VERSION 5.8 ;
BUSBITCHARS "[]" ;
DIVIDERCHAR "/" ;
UNITS
    DATABASE MICRONS 1000 ;
END UNITS

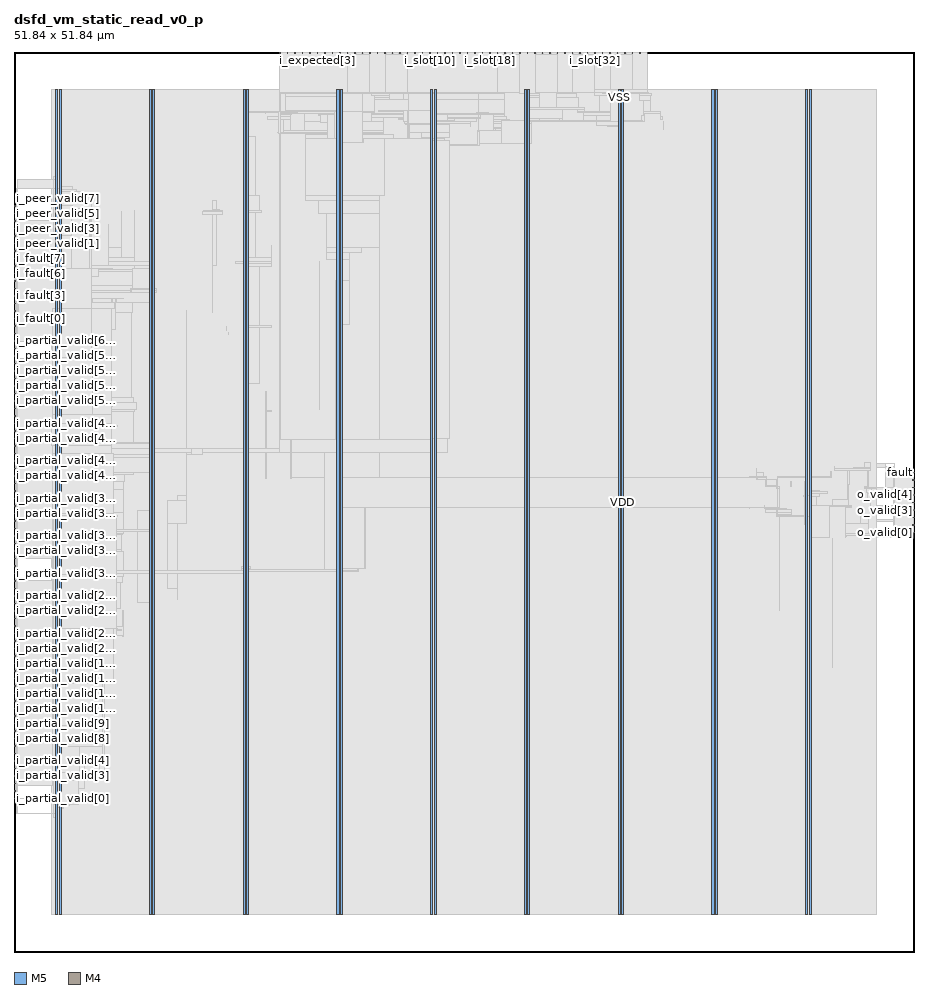
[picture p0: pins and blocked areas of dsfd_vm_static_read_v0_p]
MACRO dsfd_vm_static_read_v0_p
  FOREIGN dsfd_vm_static_read_v0_p 0 0 ;
  CLASS BLOCK ;
  SIZE 51.84 BY 51.84 ;
  PIN ck
    DIRECTION INPUT ;
    USE SIGNAL ;
    PORT
      LAYER M5 ;
        RECT  15.312 51.756 15.336 51.84 ;
    END
  END ck
  PIN fault
    DIRECTION OUTPUT ;
    USE SIGNAL ;
    PORT
      LAYER M4 ;
        RECT  51.756 27.6 51.84 27.624 ;
    END
  END fault
  PIN i_expected[0]
    DIRECTION INPUT ;
    USE SIGNAL ;
    PORT
      LAYER M5 ;
        RECT  16.176 51.756 16.2 51.84 ;
    END
  END i_expected[0]
  PIN i_expected[1]
    DIRECTION INPUT ;
    USE SIGNAL ;
    PORT
      LAYER M5 ;
        RECT  16.608 51.756 16.632 51.84 ;
    END
  END i_expected[1]
  PIN i_expected[2]
    DIRECTION INPUT ;
    USE SIGNAL ;
    PORT
      LAYER M5 ;
        RECT  17.04 51.756 17.064 51.84 ;
    END
  END i_expected[2]
  PIN i_expected[3]
    DIRECTION INPUT ;
    USE SIGNAL ;
    PORT
      LAYER M5 ;
        RECT  17.472 51.756 17.496 51.84 ;
    END
  END i_expected[3]
  PIN i_expected[4]
    DIRECTION INPUT ;
    USE SIGNAL ;
    PORT
      LAYER M5 ;
        RECT  17.904 51.756 17.928 51.84 ;
    END
  END i_expected[4]
  PIN i_expected[5]
    DIRECTION INPUT ;
    USE SIGNAL ;
    PORT
      LAYER M5 ;
        RECT  18.336 51.756 18.36 51.84 ;
    END
  END i_expected[5]
  PIN i_expected[6]
    DIRECTION INPUT ;
    USE SIGNAL ;
    PORT
      LAYER M5 ;
        RECT  18.768 51.756 18.792 51.84 ;
    END
  END i_expected[6]
  PIN i_expected[7]
    DIRECTION INPUT ;
    USE SIGNAL ;
    PORT
      LAYER M5 ;
        RECT  19.2 51.756 19.224 51.84 ;
    END
  END i_expected[7]
  PIN i_fault[0]
    DIRECTION INPUT ;
    USE SIGNAL ;
    PORT
      LAYER M4 ;
        RECT  0 36.48 0.084 36.504 ;
    END
  END i_fault[0]
  PIN i_fault[1]
    DIRECTION INPUT ;
    USE SIGNAL ;
    PORT
      LAYER M4 ;
        RECT  0 36.912 0.084 36.936 ;
    END
  END i_fault[1]
  PIN i_fault[2]
    DIRECTION INPUT ;
    USE SIGNAL ;
    PORT
      LAYER M4 ;
        RECT  0 37.344 0.084 37.368 ;
    END
  END i_fault[2]
  PIN i_fault[3]
    DIRECTION INPUT ;
    USE SIGNAL ;
    PORT
      LAYER M4 ;
        RECT  0 37.776 0.084 37.8 ;
    END
  END i_fault[3]
  PIN i_fault[4]
    DIRECTION INPUT ;
    USE SIGNAL ;
    PORT
      LAYER M4 ;
        RECT  0 38.208 0.084 38.232 ;
    END
  END i_fault[4]
  PIN i_fault[5]
    DIRECTION INPUT ;
    USE SIGNAL ;
    PORT
      LAYER M4 ;
        RECT  0 38.64 0.084 38.664 ;
    END
  END i_fault[5]
  PIN i_fault[6]
    DIRECTION INPUT ;
    USE SIGNAL ;
    PORT
      LAYER M4 ;
        RECT  0 39.072 0.084 39.096 ;
    END
  END i_fault[6]
  PIN i_fault[7]
    DIRECTION INPUT ;
    USE SIGNAL ;
    PORT
      LAYER M4 ;
        RECT  0 39.504 0.084 39.528 ;
    END
  END i_fault[7]
  PIN i_partial_valid[0]
    DIRECTION INPUT ;
    USE SIGNAL ;
    PORT
      LAYER M4 ;
        RECT  0 8.832 0.084 8.856 ;
    END
  END i_partial_valid[0]
  PIN i_partial_valid[10]
    DIRECTION INPUT ;
    USE SIGNAL ;
    PORT
      LAYER M4 ;
        RECT  0 13.152 0.084 13.176 ;
    END
  END i_partial_valid[10]
  PIN i_partial_valid[11]
    DIRECTION INPUT ;
    USE SIGNAL ;
    PORT
      LAYER M4 ;
        RECT  0 13.584 0.084 13.608 ;
    END
  END i_partial_valid[11]
  PIN i_partial_valid[12]
    DIRECTION INPUT ;
    USE SIGNAL ;
    PORT
      LAYER M4 ;
        RECT  0 14.016 0.084 14.04 ;
    END
  END i_partial_valid[12]
  PIN i_partial_valid[13]
    DIRECTION INPUT ;
    USE SIGNAL ;
    PORT
      LAYER M4 ;
        RECT  0 14.448 0.084 14.472 ;
    END
  END i_partial_valid[13]
  PIN i_partial_valid[14]
    DIRECTION INPUT ;
    USE SIGNAL ;
    PORT
      LAYER M4 ;
        RECT  0 14.88 0.084 14.904 ;
    END
  END i_partial_valid[14]
  PIN i_partial_valid[15]
    DIRECTION INPUT ;
    USE SIGNAL ;
    PORT
      LAYER M4 ;
        RECT  0 15.312 0.084 15.336 ;
    END
  END i_partial_valid[15]
  PIN i_partial_valid[16]
    DIRECTION INPUT ;
    USE SIGNAL ;
    PORT
      LAYER M4 ;
        RECT  0 15.744 0.084 15.768 ;
    END
  END i_partial_valid[16]
  PIN i_partial_valid[17]
    DIRECTION INPUT ;
    USE SIGNAL ;
    PORT
      LAYER M4 ;
        RECT  0 16.176 0.084 16.2 ;
    END
  END i_partial_valid[17]
  PIN i_partial_valid[18]
    DIRECTION INPUT ;
    USE SIGNAL ;
    PORT
      LAYER M4 ;
        RECT  0 16.608 0.084 16.632 ;
    END
  END i_partial_valid[18]
  PIN i_partial_valid[19]
    DIRECTION INPUT ;
    USE SIGNAL ;
    PORT
      LAYER M4 ;
        RECT  0 17.04 0.084 17.064 ;
    END
  END i_partial_valid[19]
  PIN i_partial_valid[1]
    DIRECTION INPUT ;
    USE SIGNAL ;
    PORT
      LAYER M4 ;
        RECT  0 9.264 0.084 9.288 ;
    END
  END i_partial_valid[1]
  PIN i_partial_valid[20]
    DIRECTION INPUT ;
    USE SIGNAL ;
    PORT
      LAYER M4 ;
        RECT  0 17.472 0.084 17.496 ;
    END
  END i_partial_valid[20]
  PIN i_partial_valid[21]
    DIRECTION INPUT ;
    USE SIGNAL ;
    PORT
      LAYER M4 ;
        RECT  0 17.904 0.084 17.928 ;
    END
  END i_partial_valid[21]
  PIN i_partial_valid[22]
    DIRECTION INPUT ;
    USE SIGNAL ;
    PORT
      LAYER M4 ;
        RECT  0 18.336 0.084 18.36 ;
    END
  END i_partial_valid[22]
  PIN i_partial_valid[23]
    DIRECTION INPUT ;
    USE SIGNAL ;
    PORT
      LAYER M4 ;
        RECT  0 18.768 0.084 18.792 ;
    END
  END i_partial_valid[23]
  PIN i_partial_valid[24]
    DIRECTION INPUT ;
    USE SIGNAL ;
    PORT
      LAYER M4 ;
        RECT  0 19.2 0.084 19.224 ;
    END
  END i_partial_valid[24]
  PIN i_partial_valid[25]
    DIRECTION INPUT ;
    USE SIGNAL ;
    PORT
      LAYER M4 ;
        RECT  0 19.632 0.084 19.656 ;
    END
  END i_partial_valid[25]
  PIN i_partial_valid[26]
    DIRECTION INPUT ;
    USE SIGNAL ;
    PORT
      LAYER M4 ;
        RECT  0 20.064 0.084 20.088 ;
    END
  END i_partial_valid[26]
  PIN i_partial_valid[27]
    DIRECTION INPUT ;
    USE SIGNAL ;
    PORT
      LAYER M4 ;
        RECT  0 20.496 0.084 20.52 ;
    END
  END i_partial_valid[27]
  PIN i_partial_valid[28]
    DIRECTION INPUT ;
    USE SIGNAL ;
    PORT
      LAYER M4 ;
        RECT  0 20.928 0.084 20.952 ;
    END
  END i_partial_valid[28]
  PIN i_partial_valid[29]
    DIRECTION INPUT ;
    USE SIGNAL ;
    PORT
      LAYER M4 ;
        RECT  0 21.36 0.084 21.384 ;
    END
  END i_partial_valid[29]
  PIN i_partial_valid[2]
    DIRECTION INPUT ;
    USE SIGNAL ;
    PORT
      LAYER M4 ;
        RECT  0 9.696 0.084 9.72 ;
    END
  END i_partial_valid[2]
  PIN i_partial_valid[30]
    DIRECTION INPUT ;
    USE SIGNAL ;
    PORT
      LAYER M4 ;
        RECT  0 21.792 0.084 21.816 ;
    END
  END i_partial_valid[30]
  PIN i_partial_valid[31]
    DIRECTION INPUT ;
    USE SIGNAL ;
    PORT
      LAYER M4 ;
        RECT  0 22.224 0.084 22.248 ;
    END
  END i_partial_valid[31]
  PIN i_partial_valid[32]
    DIRECTION INPUT ;
    USE SIGNAL ;
    PORT
      LAYER M4 ;
        RECT  0 22.656 0.084 22.68 ;
    END
  END i_partial_valid[32]
  PIN i_partial_valid[33]
    DIRECTION INPUT ;
    USE SIGNAL ;
    PORT
      LAYER M4 ;
        RECT  0 23.088 0.084 23.112 ;
    END
  END i_partial_valid[33]
  PIN i_partial_valid[34]
    DIRECTION INPUT ;
    USE SIGNAL ;
    PORT
      LAYER M4 ;
        RECT  0 23.52 0.084 23.544 ;
    END
  END i_partial_valid[34]
  PIN i_partial_valid[35]
    DIRECTION INPUT ;
    USE SIGNAL ;
    PORT
      LAYER M4 ;
        RECT  0 23.952 0.084 23.976 ;
    END
  END i_partial_valid[35]
  PIN i_partial_valid[36]
    DIRECTION INPUT ;
    USE SIGNAL ;
    PORT
      LAYER M4 ;
        RECT  0 24.384 0.084 24.408 ;
    END
  END i_partial_valid[36]
  PIN i_partial_valid[37]
    DIRECTION INPUT ;
    USE SIGNAL ;
    PORT
      LAYER M4 ;
        RECT  0 24.816 0.084 24.84 ;
    END
  END i_partial_valid[37]
  PIN i_partial_valid[38]
    DIRECTION INPUT ;
    USE SIGNAL ;
    PORT
      LAYER M4 ;
        RECT  0 25.248 0.084 25.272 ;
    END
  END i_partial_valid[38]
  PIN i_partial_valid[39]
    DIRECTION INPUT ;
    USE SIGNAL ;
    PORT
      LAYER M4 ;
        RECT  0 25.68 0.084 25.704 ;
    END
  END i_partial_valid[39]
  PIN i_partial_valid[3]
    DIRECTION INPUT ;
    USE SIGNAL ;
    PORT
      LAYER M4 ;
        RECT  0 10.128 0.084 10.152 ;
    END
  END i_partial_valid[3]
  PIN i_partial_valid[40]
    DIRECTION INPUT ;
    USE SIGNAL ;
    PORT
      LAYER M4 ;
        RECT  0 26.112 0.084 26.136 ;
    END
  END i_partial_valid[40]
  PIN i_partial_valid[41]
    DIRECTION INPUT ;
    USE SIGNAL ;
    PORT
      LAYER M4 ;
        RECT  0 26.544 0.084 26.568 ;
    END
  END i_partial_valid[41]
  PIN i_partial_valid[42]
    DIRECTION INPUT ;
    USE SIGNAL ;
    PORT
      LAYER M4 ;
        RECT  0 26.976 0.084 27 ;
    END
  END i_partial_valid[42]
  PIN i_partial_valid[43]
    DIRECTION INPUT ;
    USE SIGNAL ;
    PORT
      LAYER M4 ;
        RECT  0 27.408 0.084 27.432 ;
    END
  END i_partial_valid[43]
  PIN i_partial_valid[44]
    DIRECTION INPUT ;
    USE SIGNAL ;
    PORT
      LAYER M4 ;
        RECT  0 27.84 0.084 27.864 ;
    END
  END i_partial_valid[44]
  PIN i_partial_valid[45]
    DIRECTION INPUT ;
    USE SIGNAL ;
    PORT
      LAYER M4 ;
        RECT  0 28.272 0.084 28.296 ;
    END
  END i_partial_valid[45]
  PIN i_partial_valid[46]
    DIRECTION INPUT ;
    USE SIGNAL ;
    PORT
      LAYER M4 ;
        RECT  0 28.704 0.084 28.728 ;
    END
  END i_partial_valid[46]
  PIN i_partial_valid[47]
    DIRECTION INPUT ;
    USE SIGNAL ;
    PORT
      LAYER M4 ;
        RECT  0 29.136 0.084 29.16 ;
    END
  END i_partial_valid[47]
  PIN i_partial_valid[48]
    DIRECTION INPUT ;
    USE SIGNAL ;
    PORT
      LAYER M4 ;
        RECT  0 29.568 0.084 29.592 ;
    END
  END i_partial_valid[48]
  PIN i_partial_valid[49]
    DIRECTION INPUT ;
    USE SIGNAL ;
    PORT
      LAYER M4 ;
        RECT  0 30 0.084 30.024 ;
    END
  END i_partial_valid[49]
  PIN i_partial_valid[4]
    DIRECTION INPUT ;
    USE SIGNAL ;
    PORT
      LAYER M4 ;
        RECT  0 10.56 0.084 10.584 ;
    END
  END i_partial_valid[4]
  PIN i_partial_valid[50]
    DIRECTION INPUT ;
    USE SIGNAL ;
    PORT
      LAYER M4 ;
        RECT  0 30.432 0.084 30.456 ;
    END
  END i_partial_valid[50]
  PIN i_partial_valid[51]
    DIRECTION INPUT ;
    USE SIGNAL ;
    PORT
      LAYER M4 ;
        RECT  0 30.864 0.084 30.888 ;
    END
  END i_partial_valid[51]
  PIN i_partial_valid[52]
    DIRECTION INPUT ;
    USE SIGNAL ;
    PORT
      LAYER M4 ;
        RECT  0 31.296 0.084 31.32 ;
    END
  END i_partial_valid[52]
  PIN i_partial_valid[53]
    DIRECTION INPUT ;
    USE SIGNAL ;
    PORT
      LAYER M4 ;
        RECT  0 31.728 0.084 31.752 ;
    END
  END i_partial_valid[53]
  PIN i_partial_valid[54]
    DIRECTION INPUT ;
    USE SIGNAL ;
    PORT
      LAYER M4 ;
        RECT  0 32.16 0.084 32.184 ;
    END
  END i_partial_valid[54]
  PIN i_partial_valid[55]
    DIRECTION INPUT ;
    USE SIGNAL ;
    PORT
      LAYER M4 ;
        RECT  0 32.592 0.084 32.616 ;
    END
  END i_partial_valid[55]
  PIN i_partial_valid[56]
    DIRECTION INPUT ;
    USE SIGNAL ;
    PORT
      LAYER M4 ;
        RECT  0 33.024 0.084 33.048 ;
    END
  END i_partial_valid[56]
  PIN i_partial_valid[57]
    DIRECTION INPUT ;
    USE SIGNAL ;
    PORT
      LAYER M4 ;
        RECT  0 33.456 0.084 33.48 ;
    END
  END i_partial_valid[57]
  PIN i_partial_valid[58]
    DIRECTION INPUT ;
    USE SIGNAL ;
    PORT
      LAYER M4 ;
        RECT  0 33.888 0.084 33.912 ;
    END
  END i_partial_valid[58]
  PIN i_partial_valid[59]
    DIRECTION INPUT ;
    USE SIGNAL ;
    PORT
      LAYER M4 ;
        RECT  0 34.32 0.084 34.344 ;
    END
  END i_partial_valid[59]
  PIN i_partial_valid[5]
    DIRECTION INPUT ;
    USE SIGNAL ;
    PORT
      LAYER M4 ;
        RECT  0 10.992 0.084 11.016 ;
    END
  END i_partial_valid[5]
  PIN i_partial_valid[60]
    DIRECTION INPUT ;
    USE SIGNAL ;
    PORT
      LAYER M4 ;
        RECT  0 34.752 0.084 34.776 ;
    END
  END i_partial_valid[60]
  PIN i_partial_valid[61]
    DIRECTION INPUT ;
    USE SIGNAL ;
    PORT
      LAYER M4 ;
        RECT  0 35.184 0.084 35.208 ;
    END
  END i_partial_valid[61]
  PIN i_partial_valid[62]
    DIRECTION INPUT ;
    USE SIGNAL ;
    PORT
      LAYER M4 ;
        RECT  0 35.616 0.084 35.64 ;
    END
  END i_partial_valid[62]
  PIN i_partial_valid[63]
    DIRECTION INPUT ;
    USE SIGNAL ;
    PORT
      LAYER M4 ;
        RECT  0 36.048 0.084 36.072 ;
    END
  END i_partial_valid[63]
  PIN i_partial_valid[6]
    DIRECTION INPUT ;
    USE SIGNAL ;
    PORT
      LAYER M4 ;
        RECT  0 11.424 0.084 11.448 ;
    END
  END i_partial_valid[6]
  PIN i_partial_valid[7]
    DIRECTION INPUT ;
    USE SIGNAL ;
    PORT
      LAYER M4 ;
        RECT  0 11.856 0.084 11.88 ;
    END
  END i_partial_valid[7]
  PIN i_partial_valid[8]
    DIRECTION INPUT ;
    USE SIGNAL ;
    PORT
      LAYER M4 ;
        RECT  0 12.288 0.084 12.312 ;
    END
  END i_partial_valid[8]
  PIN i_partial_valid[9]
    DIRECTION INPUT ;
    USE SIGNAL ;
    PORT
      LAYER M4 ;
        RECT  0 12.72 0.084 12.744 ;
    END
  END i_partial_valid[9]
  PIN i_peer_valid[0]
    DIRECTION INPUT ;
    USE SIGNAL ;
    PORT
      LAYER M4 ;
        RECT  0 39.936 0.084 39.96 ;
    END
  END i_peer_valid[0]
  PIN i_peer_valid[1]
    DIRECTION INPUT ;
    USE SIGNAL ;
    PORT
      LAYER M4 ;
        RECT  0 40.368 0.084 40.392 ;
    END
  END i_peer_valid[1]
  PIN i_peer_valid[2]
    DIRECTION INPUT ;
    USE SIGNAL ;
    PORT
      LAYER M4 ;
        RECT  0 40.8 0.084 40.824 ;
    END
  END i_peer_valid[2]
  PIN i_peer_valid[3]
    DIRECTION INPUT ;
    USE SIGNAL ;
    PORT
      LAYER M4 ;
        RECT  0 41.232 0.084 41.256 ;
    END
  END i_peer_valid[3]
  PIN i_peer_valid[4]
    DIRECTION INPUT ;
    USE SIGNAL ;
    PORT
      LAYER M4 ;
        RECT  0 41.664 0.084 41.688 ;
    END
  END i_peer_valid[4]
  PIN i_peer_valid[5]
    DIRECTION INPUT ;
    USE SIGNAL ;
    PORT
      LAYER M4 ;
        RECT  0 42.096 0.084 42.12 ;
    END
  END i_peer_valid[5]
  PIN i_peer_valid[6]
    DIRECTION INPUT ;
    USE SIGNAL ;
    PORT
      LAYER M4 ;
        RECT  0 42.528 0.084 42.552 ;
    END
  END i_peer_valid[6]
  PIN i_peer_valid[7]
    DIRECTION INPUT ;
    USE SIGNAL ;
    PORT
      LAYER M4 ;
        RECT  0 42.96 0.084 42.984 ;
    END
  END i_peer_valid[7]
  PIN i_slot[0]
    DIRECTION INPUT ;
    USE SIGNAL ;
    PORT
      LAYER M5 ;
        RECT  19.632 51.756 19.656 51.84 ;
    END
  END i_slot[0]
  PIN i_slot[10]
    DIRECTION INPUT ;
    USE SIGNAL ;
    PORT
      LAYER M5 ;
        RECT  23.952 51.756 23.976 51.84 ;
    END
  END i_slot[10]
  PIN i_slot[11]
    DIRECTION INPUT ;
    USE SIGNAL ;
    PORT
      LAYER M5 ;
        RECT  24.384 51.756 24.408 51.84 ;
    END
  END i_slot[11]
  PIN i_slot[12]
    DIRECTION INPUT ;
    USE SIGNAL ;
    PORT
      LAYER M5 ;
        RECT  24.816 51.756 24.84 51.84 ;
    END
  END i_slot[12]
  PIN i_slot[13]
    DIRECTION INPUT ;
    USE SIGNAL ;
    PORT
      LAYER M5 ;
        RECT  25.248 51.756 25.272 51.84 ;
    END
  END i_slot[13]
  PIN i_slot[14]
    DIRECTION INPUT ;
    USE SIGNAL ;
    PORT
      LAYER M5 ;
        RECT  25.68 51.756 25.704 51.84 ;
    END
  END i_slot[14]
  PIN i_slot[15]
    DIRECTION INPUT ;
    USE SIGNAL ;
    PORT
      LAYER M5 ;
        RECT  26.112 51.756 26.136 51.84 ;
    END
  END i_slot[15]
  PIN i_slot[16]
    DIRECTION INPUT ;
    USE SIGNAL ;
    PORT
      LAYER M5 ;
        RECT  26.544 51.756 26.568 51.84 ;
    END
  END i_slot[16]
  PIN i_slot[17]
    DIRECTION INPUT ;
    USE SIGNAL ;
    PORT
      LAYER M5 ;
        RECT  26.976 51.756 27 51.84 ;
    END
  END i_slot[17]
  PIN i_slot[18]
    DIRECTION INPUT ;
    USE SIGNAL ;
    PORT
      LAYER M5 ;
        RECT  27.408 51.756 27.432 51.84 ;
    END
  END i_slot[18]
  PIN i_slot[19]
    DIRECTION INPUT ;
    USE SIGNAL ;
    PORT
      LAYER M5 ;
        RECT  27.84 51.756 27.864 51.84 ;
    END
  END i_slot[19]
  PIN i_slot[1]
    DIRECTION INPUT ;
    USE SIGNAL ;
    PORT
      LAYER M5 ;
        RECT  20.064 51.756 20.088 51.84 ;
    END
  END i_slot[1]
  PIN i_slot[20]
    DIRECTION INPUT ;
    USE SIGNAL ;
    PORT
      LAYER M5 ;
        RECT  28.272 51.756 28.296 51.84 ;
    END
  END i_slot[20]
  PIN i_slot[21]
    DIRECTION INPUT ;
    USE SIGNAL ;
    PORT
      LAYER M5 ;
        RECT  28.704 51.756 28.728 51.84 ;
    END
  END i_slot[21]
  PIN i_slot[22]
    DIRECTION INPUT ;
    USE SIGNAL ;
    PORT
      LAYER M5 ;
        RECT  29.136 51.756 29.16 51.84 ;
    END
  END i_slot[22]
  PIN i_slot[23]
    DIRECTION INPUT ;
    USE SIGNAL ;
    PORT
      LAYER M5 ;
        RECT  29.568 51.756 29.592 51.84 ;
    END
  END i_slot[23]
  PIN i_slot[24]
    DIRECTION INPUT ;
    USE SIGNAL ;
    PORT
      LAYER M5 ;
        RECT  30 51.756 30.024 51.84 ;
    END
  END i_slot[24]
  PIN i_slot[25]
    DIRECTION INPUT ;
    USE SIGNAL ;
    PORT
      LAYER M5 ;
        RECT  30.432 51.756 30.456 51.84 ;
    END
  END i_slot[25]
  PIN i_slot[26]
    DIRECTION INPUT ;
    USE SIGNAL ;
    PORT
      LAYER M5 ;
        RECT  30.864 51.756 30.888 51.84 ;
    END
  END i_slot[26]
  PIN i_slot[27]
    DIRECTION INPUT ;
    USE SIGNAL ;
    PORT
      LAYER M5 ;
        RECT  31.296 51.756 31.32 51.84 ;
    END
  END i_slot[27]
  PIN i_slot[28]
    DIRECTION INPUT ;
    USE SIGNAL ;
    PORT
      LAYER M5 ;
        RECT  31.728 51.756 31.752 51.84 ;
    END
  END i_slot[28]
  PIN i_slot[29]
    DIRECTION INPUT ;
    USE SIGNAL ;
    PORT
      LAYER M5 ;
        RECT  32.16 51.756 32.184 51.84 ;
    END
  END i_slot[29]
  PIN i_slot[2]
    DIRECTION INPUT ;
    USE SIGNAL ;
    PORT
      LAYER M5 ;
        RECT  20.496 51.756 20.52 51.84 ;
    END
  END i_slot[2]
  PIN i_slot[30]
    DIRECTION INPUT ;
    USE SIGNAL ;
    PORT
      LAYER M5 ;
        RECT  32.592 51.756 32.616 51.84 ;
    END
  END i_slot[30]
  PIN i_slot[31]
    DIRECTION INPUT ;
    USE SIGNAL ;
    PORT
      LAYER M5 ;
        RECT  33.024 51.756 33.048 51.84 ;
    END
  END i_slot[31]
  PIN i_slot[32]
    DIRECTION INPUT ;
    USE SIGNAL ;
    PORT
      LAYER M5 ;
        RECT  33.456 51.756 33.48 51.84 ;
    END
  END i_slot[32]
  PIN i_slot[33]
    DIRECTION INPUT ;
    USE SIGNAL ;
    PORT
      LAYER M5 ;
        RECT  33.888 51.756 33.912 51.84 ;
    END
  END i_slot[33]
  PIN i_slot[34]
    DIRECTION INPUT ;
    USE SIGNAL ;
    PORT
      LAYER M5 ;
        RECT  34.32 51.756 34.344 51.84 ;
    END
  END i_slot[34]
  PIN i_slot[35]
    DIRECTION INPUT ;
    USE SIGNAL ;
    PORT
      LAYER M5 ;
        RECT  34.752 51.756 34.776 51.84 ;
    END
  END i_slot[35]
  PIN i_slot[36]
    DIRECTION INPUT ;
    USE SIGNAL ;
    PORT
      LAYER M5 ;
        RECT  35.184 51.756 35.208 51.84 ;
    END
  END i_slot[36]
  PIN i_slot[37]
    DIRECTION INPUT ;
    USE SIGNAL ;
    PORT
      LAYER M5 ;
        RECT  35.616 51.756 35.64 51.84 ;
    END
  END i_slot[37]
  PIN i_slot[38]
    DIRECTION INPUT ;
    USE SIGNAL ;
    PORT
      LAYER M5 ;
        RECT  36.048 51.756 36.072 51.84 ;
    END
  END i_slot[38]
  PIN i_slot[39]
    DIRECTION INPUT ;
    USE SIGNAL ;
    PORT
      LAYER M5 ;
        RECT  36.48 51.756 36.504 51.84 ;
    END
  END i_slot[39]
  PIN i_slot[3]
    DIRECTION INPUT ;
    USE SIGNAL ;
    PORT
      LAYER M5 ;
        RECT  20.928 51.756 20.952 51.84 ;
    END
  END i_slot[3]
  PIN i_slot[4]
    DIRECTION INPUT ;
    USE SIGNAL ;
    PORT
      LAYER M5 ;
        RECT  21.36 51.756 21.384 51.84 ;
    END
  END i_slot[4]
  PIN i_slot[5]
    DIRECTION INPUT ;
    USE SIGNAL ;
    PORT
      LAYER M5 ;
        RECT  21.792 51.756 21.816 51.84 ;
    END
  END i_slot[5]
  PIN i_slot[6]
    DIRECTION INPUT ;
    USE SIGNAL ;
    PORT
      LAYER M5 ;
        RECT  22.224 51.756 22.248 51.84 ;
    END
  END i_slot[6]
  PIN i_slot[7]
    DIRECTION INPUT ;
    USE SIGNAL ;
    PORT
      LAYER M5 ;
        RECT  22.656 51.756 22.68 51.84 ;
    END
  END i_slot[7]
  PIN i_slot[8]
    DIRECTION INPUT ;
    USE SIGNAL ;
    PORT
      LAYER M5 ;
        RECT  23.088 51.756 23.112 51.84 ;
    END
  END i_slot[8]
  PIN i_slot[9]
    DIRECTION INPUT ;
    USE SIGNAL ;
    PORT
      LAYER M5 ;
        RECT  23.52 51.756 23.544 51.84 ;
    END
  END i_slot[9]
  PIN o_valid[0]
    DIRECTION OUTPUT ;
    USE SIGNAL ;
    PORT
      LAYER M4 ;
        RECT  51.756 24.144 51.84 24.168 ;
    END
  END o_valid[0]
  PIN o_valid[1]
    DIRECTION OUTPUT ;
    USE SIGNAL ;
    PORT
      LAYER M4 ;
        RECT  51.756 24.576 51.84 24.6 ;
    END
  END o_valid[1]
  PIN o_valid[2]
    DIRECTION OUTPUT ;
    USE SIGNAL ;
    PORT
      LAYER M4 ;
        RECT  51.756 25.008 51.84 25.032 ;
    END
  END o_valid[2]
  PIN o_valid[3]
    DIRECTION OUTPUT ;
    USE SIGNAL ;
    PORT
      LAYER M4 ;
        RECT  51.756 25.44 51.84 25.464 ;
    END
  END o_valid[3]
  PIN o_valid[4]
    DIRECTION OUTPUT ;
    USE SIGNAL ;
    PORT
      LAYER M4 ;
        RECT  51.756 25.872 51.84 25.896 ;
    END
  END o_valid[4]
  PIN o_valid[5]
    DIRECTION OUTPUT ;
    USE SIGNAL ;
    PORT
      LAYER M4 ;
        RECT  51.756 26.304 51.84 26.328 ;
    END
  END o_valid[5]
  PIN o_valid[6]
    DIRECTION OUTPUT ;
    USE SIGNAL ;
    PORT
      LAYER M4 ;
        RECT  51.756 26.736 51.84 26.76 ;
    END
  END o_valid[6]
  PIN o_valid[7]
    DIRECTION OUTPUT ;
    USE SIGNAL ;
    PORT
      LAYER M4 ;
        RECT  51.756 27.168 51.84 27.192 ;
    END
  END o_valid[7]
  PIN rst_n
    DIRECTION INPUT ;
    USE SIGNAL ;
    PORT
      LAYER M5 ;
        RECT  15.744 51.756 15.768 51.84 ;
    END
  END rst_n
  PIN VDD
    DIRECTION INOUT ;
    USE POWER ;
    PORT
      LAYER M5 ;
        RECT  45.792 2.151 45.912 49.689 ;
        RECT  40.392 2.151 40.512 49.689 ;
        RECT  34.992 2.151 35.112 49.689 ;
        RECT  29.592 2.151 29.712 49.689 ;
        RECT  24.192 2.151 24.312 49.689 ;
        RECT  18.792 2.151 18.912 49.689 ;
        RECT  13.392 2.151 13.512 49.689 ;
        RECT  7.992 2.151 8.112 49.689 ;
        RECT  2.592 2.151 2.712 49.689 ;
    END
  END VDD
  PIN VSS
    DIRECTION INOUT ;
    USE GROUND ;
    PORT
      LAYER M5 ;
        RECT  45.6 2.137 45.72 49.703 ;
        RECT  40.2 2.137 40.32 49.703 ;
        RECT  34.8 2.137 34.92 49.703 ;
        RECT  29.4 2.137 29.52 49.703 ;
        RECT  24 2.137 24.12 49.703 ;
        RECT  18.6 2.137 18.72 49.703 ;
        RECT  13.2 2.137 13.32 49.703 ;
        RECT  7.8 2.137 7.92 49.703 ;
        RECT  2.4 2.137 2.52 49.703 ;
    END
  END VSS
  # OT_OBS_CLOSED layer=M5 d_um=1.536 added=51
  OBS
    LAYER RVTN ;
     RECT  2.16 2.16 49.68 2.295 ;
     RECT  2.16 2.565 49.68 2.835 ;
     RECT  2.16 3.105 49.68 3.375 ;
     RECT  2.16 3.645 49.68 3.915 ;
     RECT  2.16 4.185 49.68 4.455 ;
     RECT  2.16 4.725 49.68 4.995 ;
     RECT  2.16 5.265 49.68 5.535 ;
     RECT  2.16 5.805 49.68 6.075 ;
     RECT  2.16 6.345 49.68 6.615 ;
     RECT  2.16 6.885 49.68 7.155 ;
     RECT  2.16 7.425 49.68 7.695 ;
     RECT  2.16 7.965 49.68 8.235 ;
     RECT  2.16 8.505 49.68 8.775 ;
     RECT  2.16 9.045 49.68 9.315 ;
     RECT  2.16 9.585 49.68 9.855 ;
     RECT  2.16 10.125 49.68 10.395 ;
     RECT  2.16 10.665 49.68 10.935 ;
     RECT  2.16 11.205 49.68 11.475 ;
     RECT  2.16 11.745 49.68 12.015 ;
     RECT  2.16 12.285 49.68 12.555 ;
     RECT  2.16 12.825 49.68 13.095 ;
     RECT  2.16 13.365 49.68 13.635 ;
     RECT  2.16 13.905 49.68 14.175 ;
     RECT  2.16 14.445 49.68 14.715 ;
     RECT  2.16 14.985 49.68 15.255 ;
     RECT  2.16 15.525 49.68 15.795 ;
     RECT  2.16 16.065 49.68 16.335 ;
     RECT  2.16 16.605 49.68 16.875 ;
     RECT  2.16 17.145 49.68 17.415 ;
     RECT  2.16 17.685 49.68 17.955 ;
     RECT  2.16 18.225 49.68 18.495 ;
     RECT  2.16 18.765 49.68 19.035 ;
     RECT  2.16 19.305 49.68 19.575 ;
     RECT  2.16 19.845 49.68 20.115 ;
     RECT  2.16 20.385 49.68 20.655 ;
     RECT  2.16 20.925 49.68 21.195 ;
     RECT  2.16 21.465 49.68 21.735 ;
     RECT  2.16 22.005 49.68 22.275 ;
     RECT  2.16 22.545 49.68 22.815 ;
     RECT  2.16 23.085 49.68 23.355 ;
     RECT  2.16 23.625 49.68 23.895 ;
     RECT  2.16 24.165 49.68 24.435 ;
     RECT  2.16 24.705 49.68 24.975 ;
     RECT  2.16 25.245 49.68 25.515 ;
     RECT  2.16 25.785 49.68 26.055 ;
     RECT  2.16 26.325 49.68 26.595 ;
     RECT  2.16 26.865 49.68 27.135 ;
     RECT  2.16 27.405 49.68 27.675 ;
     RECT  2.16 27.945 49.68 28.215 ;
     RECT  2.16 28.485 49.68 28.755 ;
     RECT  2.16 29.025 49.68 29.295 ;
     RECT  2.16 29.565 49.68 29.835 ;
     RECT  2.16 30.105 49.68 30.375 ;
     RECT  2.16 30.645 49.68 30.915 ;
     RECT  2.16 31.185 49.68 31.455 ;
     RECT  2.16 31.725 49.68 31.995 ;
     RECT  2.16 32.265 49.68 32.535 ;
     RECT  2.16 32.805 49.68 33.075 ;
     RECT  2.16 33.345 49.68 33.615 ;
     RECT  2.16 33.885 49.68 34.155 ;
     RECT  2.16 34.425 49.68 34.695 ;
     RECT  2.16 34.965 49.68 35.235 ;
     RECT  2.16 35.505 49.68 35.775 ;
     RECT  2.16 36.045 49.68 36.315 ;
     RECT  2.16 36.585 49.68 36.855 ;
     RECT  2.16 37.125 49.68 37.395 ;
     RECT  2.16 37.665 49.68 37.935 ;
     RECT  2.16 38.205 49.68 38.475 ;
     RECT  2.16 38.745 49.68 39.015 ;
     RECT  2.16 39.285 49.68 39.555 ;
     RECT  2.16 39.825 49.68 40.095 ;
     RECT  2.16 40.365 49.68 40.635 ;
     RECT  2.16 40.905 49.68 41.175 ;
     RECT  2.16 41.445 49.68 41.715 ;
     RECT  2.16 41.985 49.68 42.255 ;
     RECT  2.16 42.525 49.68 42.795 ;
     RECT  2.16 43.065 49.68 43.335 ;
     RECT  2.16 43.605 49.68 43.875 ;
     RECT  2.16 44.145 49.68 44.415 ;
     RECT  2.16 44.685 49.68 44.955 ;
     RECT  2.16 45.225 49.68 45.495 ;
     RECT  2.16 45.765 49.68 46.035 ;
     RECT  2.16 46.305 49.68 46.575 ;
     RECT  2.16 46.845 49.68 47.115 ;
     RECT  2.16 47.385 49.68 47.655 ;
     RECT  2.16 47.925 49.68 48.195 ;
     RECT  2.16 48.465 49.68 48.735 ;
     RECT  2.16 49.005 49.68 49.275 ;
     RECT  2.16 49.545 49.68 49.68 ;
    LAYER RVTP ;
     RECT  2.16 2.295 49.68 2.565 ;
     RECT  2.16 2.835 49.68 3.105 ;
     RECT  2.16 3.375 49.68 3.645 ;
     RECT  2.16 3.915 49.68 4.185 ;
     RECT  2.16 4.455 49.68 4.725 ;
     RECT  2.16 4.995 49.68 5.265 ;
     RECT  2.16 5.535 49.68 5.805 ;
     RECT  2.16 6.075 49.68 6.345 ;
     RECT  2.16 6.615 49.68 6.885 ;
     RECT  2.16 7.155 49.68 7.425 ;
     RECT  2.16 7.695 49.68 7.965 ;
     RECT  2.16 8.235 49.68 8.505 ;
     RECT  2.16 8.775 49.68 9.045 ;
     RECT  2.16 9.315 49.68 9.585 ;
     RECT  2.16 9.855 49.68 10.125 ;
     RECT  2.16 10.395 49.68 10.665 ;
     RECT  2.16 10.935 49.68 11.205 ;
     RECT  2.16 11.475 49.68 11.745 ;
     RECT  2.16 12.015 49.68 12.285 ;
     RECT  2.16 12.555 49.68 12.825 ;
     RECT  2.16 13.095 49.68 13.365 ;
     RECT  2.16 13.635 49.68 13.905 ;
     RECT  2.16 14.175 49.68 14.445 ;
     RECT  2.16 14.715 49.68 14.985 ;
     RECT  2.16 15.255 49.68 15.525 ;
     RECT  2.16 15.795 49.68 16.065 ;
     RECT  2.16 16.335 49.68 16.605 ;
     RECT  2.16 16.875 49.68 17.145 ;
     RECT  2.16 17.415 49.68 17.685 ;
     RECT  2.16 17.955 49.68 18.225 ;
     RECT  2.16 18.495 49.68 18.765 ;
     RECT  2.16 19.035 49.68 19.305 ;
     RECT  2.16 19.575 49.68 19.845 ;
     RECT  2.16 20.115 49.68 20.385 ;
     RECT  2.16 20.655 49.68 20.925 ;
     RECT  2.16 21.195 49.68 21.465 ;
     RECT  2.16 21.735 49.68 22.005 ;
     RECT  2.16 22.275 49.68 22.545 ;
     RECT  2.16 22.815 49.68 23.085 ;
     RECT  2.16 23.355 49.68 23.625 ;
     RECT  2.16 23.895 49.68 24.165 ;
     RECT  2.16 24.435 49.68 24.705 ;
     RECT  2.16 24.975 49.68 25.245 ;
     RECT  2.16 25.515 49.68 25.785 ;
     RECT  2.16 26.055 49.68 26.325 ;
     RECT  2.16 26.595 49.68 26.865 ;
     RECT  2.16 27.135 49.68 27.405 ;
     RECT  2.16 27.675 49.68 27.945 ;
     RECT  2.16 28.215 49.68 28.485 ;
     RECT  2.16 28.755 49.68 29.025 ;
     RECT  2.16 29.295 49.68 29.565 ;
     RECT  2.16 29.835 49.68 30.105 ;
     RECT  2.16 30.375 49.68 30.645 ;
     RECT  2.16 30.915 49.68 31.185 ;
     RECT  2.16 31.455 49.68 31.725 ;
     RECT  2.16 31.995 49.68 32.265 ;
     RECT  2.16 32.535 49.68 32.805 ;
     RECT  2.16 33.075 49.68 33.345 ;
     RECT  2.16 33.615 49.68 33.885 ;
     RECT  2.16 34.155 49.68 34.425 ;
     RECT  2.16 34.695 49.68 34.965 ;
     RECT  2.16 35.235 49.68 35.505 ;
     RECT  2.16 35.775 49.68 36.045 ;
     RECT  2.16 36.315 49.68 36.585 ;
     RECT  2.16 36.855 49.68 37.125 ;
     RECT  2.16 37.395 49.68 37.665 ;
     RECT  2.16 37.935 49.68 38.205 ;
     RECT  2.16 38.475 49.68 38.745 ;
     RECT  2.16 39.015 49.68 39.285 ;
     RECT  2.16 39.555 49.68 39.825 ;
     RECT  2.16 40.095 49.68 40.365 ;
     RECT  2.16 40.635 49.68 40.905 ;
     RECT  2.16 41.175 49.68 41.445 ;
     RECT  2.16 41.715 49.68 41.985 ;
     RECT  2.16 42.255 49.68 42.525 ;
     RECT  2.16 42.795 49.68 43.065 ;
     RECT  2.16 43.335 49.68 43.605 ;
     RECT  2.16 43.875 49.68 44.145 ;
     RECT  2.16 44.415 49.68 44.685 ;
     RECT  2.16 44.955 49.68 45.225 ;
     RECT  2.16 45.495 49.68 45.765 ;
     RECT  2.16 46.035 49.68 46.305 ;
     RECT  2.16 46.575 49.68 46.845 ;
     RECT  2.16 47.115 49.68 47.385 ;
     RECT  2.16 47.655 49.68 47.925 ;
     RECT  2.16 48.195 49.68 48.465 ;
     RECT  2.16 48.735 49.68 49.005 ;
     RECT  2.16 49.275 49.68 49.545 ;
    LAYER M1 ;
     RECT  2.16 2.151 49.68 49.689 ;
    LAYER M2 ;
     RECT  0.031 38.682 0.131 38.772 ;
     RECT  0.103 8.82 2.16 8.838 ;
     RECT  0.131 38.682 2.16 38.7 ;
     RECT  2.16 2.151 49.68 49.689 ;
     RECT  49.68 27.918 50.207 28.134 ;
     RECT  49.68 24.786 50.675 24.894 ;
     RECT  49.68 26.496 50.675 26.784 ;
     RECT  50.675 24.876 50.711 24.894 ;
     RECT  49.68 25.686 50.711 25.704 ;
     RECT  50.675 26.496 50.711 26.514 ;
     RECT  50.207 28.116 50.711 28.134 ;
     RECT  49.68 23.904 50.747 23.922 ;
    LAYER M3 ;
     RECT  2.415 2.143 2.505 2.413 ;
     RECT  7.815 2.143 7.905 2.413 ;
     RECT  13.215 2.143 13.305 2.413 ;
     RECT  18.615 2.143 18.705 2.413 ;
     RECT  24.015 2.143 24.105 2.413 ;
     RECT  29.415 2.143 29.505 2.413 ;
     RECT  34.815 2.143 34.905 2.413 ;
     RECT  40.215 2.143 40.305 2.413 ;
     RECT  45.615 2.143 45.705 2.413 ;
     RECT  2.415 2.413 2.697 7.735 ;
     RECT  2.304 7.735 2.697 8.239 ;
     RECT  2.304 8.239 2.862 8.437 ;
     RECT  2.304 8.437 3.222 8.473 ;
     RECT  2.304 8.473 3.69 8.525 ;
     RECT  0.108 8.815 0.126 9.293 ;
     RECT  2.304 8.525 3.402 9.307 ;
     RECT  2.304 9.307 3.474 9.391 ;
     RECT  4.896 10.201 4.914 10.471 ;
     RECT  2.304 9.391 4.086 11.281 ;
     RECT  4.896 10.471 5.238 11.281 ;
     RECT  2.304 11.281 5.238 16.105 ;
     RECT  2.268 16.105 5.238 16.501 ;
     RECT  2.268 16.501 5.31 16.541 ;
     RECT  2.268 16.541 5.238 17.725 ;
     RECT  2.232 17.725 5.238 18.059 ;
     RECT  2.268 18.059 5.238 18.235 ;
     RECT  6.264 18.193 6.282 18.235 ;
     RECT  2.268 18.235 6.282 18.761 ;
     RECT  2.268 18.761 5.346 19.543 ;
     RECT  6.264 18.761 6.282 19.679 ;
     RECT  2.268 19.543 5.526 19.813 ;
     RECT  7.815 2.413 8.097 20.155 ;
     RECT  9.396 20.281 9.414 20.965 ;
     RECT  2.268 19.813 6.138 21.271 ;
     RECT  2.268 21.271 6.246 21.631 ;
     RECT  13.215 2.413 13.497 21.787 ;
     RECT  13.104 21.787 13.497 22.081 ;
     RECT  19.8 21.931 19.818 22.081 ;
     RECT  13.104 22.081 13.626 22.199 ;
     RECT  19.8 22.081 20.214 22.199 ;
     RECT  44.064 19.651 44.082 23.053 ;
     RECT  2.268 21.631 6.282 23.081 ;
     RECT  2.268 23.081 6.21 23.179 ;
     RECT  47.124 16.411 47.142 23.819 ;
     RECT  46.944 23.893 46.962 23.933 ;
     RECT  47.88 23.899 47.898 23.935 ;
     RECT  47.88 23.935 47.934 23.971 ;
     RECT  49.356 23.935 49.374 23.971 ;
     RECT  2.232 23.179 6.21 24.061 ;
     RECT  47.88 23.971 49.374 24.089 ;
     RECT  2.232 24.061 6.246 24.133 ;
     RECT  50.724 23.899 50.742 24.173 ;
     RECT  2.232 24.133 6.318 24.241 ;
     RECT  7.092 20.155 8.097 24.241 ;
     RECT  2.232 24.241 8.097 24.359 ;
     RECT  45.615 2.413 45.897 24.619 ;
     RECT  45.54 24.619 45.897 24.637 ;
     RECT  8.82 20.965 9.414 24.673 ;
     RECT  47.88 24.089 49.23 24.701 ;
     RECT  50.688 24.571 50.706 24.781 ;
     RECT  45.54 24.637 46.386 24.935 ;
     RECT  50.652 24.781 50.706 25.037 ;
     RECT  44.064 23.053 44.118 25.099 ;
     RECT  45.54 24.935 46.206 25.133 ;
     RECT  48.744 24.701 49.23 25.169 ;
     RECT  43.92 25.099 44.118 25.177 ;
     RECT  2.232 24.359 6.318 25.313 ;
     RECT  43.92 25.177 44.766 25.321 ;
     RECT  7.092 24.359 8.097 25.439 ;
     RECT  43.308 25.321 44.766 25.475 ;
     RECT  43.308 25.475 44.514 25.547 ;
     RECT  43.308 25.547 44.118 25.555 ;
     RECT  47.88 24.701 47.898 25.591 ;
     RECT  42.372 25.555 42.39 25.613 ;
     RECT  43.2 25.555 44.118 25.613 ;
     RECT  47.88 25.591 48.222 25.675 ;
     RECT  43.2 25.613 43.218 25.709 ;
     RECT  47.16 25.675 48.222 25.709 ;
     RECT  8.82 24.673 9.954 25.979 ;
     RECT  47.16 25.709 48.042 26.051 ;
     RECT  47.88 26.051 48.042 26.087 ;
     RECT  49.32 25.681 49.338 26.131 ;
     RECT  45.615 25.133 46.206 26.251 ;
     RECT  45.54 26.251 46.206 26.257 ;
     RECT  50.688 25.037 50.706 26.299 ;
     RECT  9.396 25.979 9.954 26.321 ;
     RECT  45.54 26.257 46.386 26.401 ;
     RECT  49.176 26.131 49.338 26.401 ;
     RECT  49.176 26.401 49.374 26.491 ;
     RECT  45.54 26.401 46.854 26.519 ;
     RECT  45.54 26.519 46.386 26.555 ;
     RECT  2.268 25.313 6.318 26.635 ;
     RECT  43.992 25.613 44.118 26.671 ;
     RECT  49.104 26.491 49.374 26.671 ;
     RECT  48.996 26.671 49.626 26.765 ;
     RECT  43.92 26.671 44.118 26.789 ;
     RECT  48.996 26.765 49.194 26.789 ;
     RECT  50.652 26.299 50.706 26.789 ;
     RECT  49.104 26.789 49.194 26.825 ;
     RECT  43.92 26.789 43.938 26.833 ;
     RECT  43.308 26.833 43.938 26.861 ;
     RECT  47.988 26.087 48.042 26.905 ;
     RECT  45.54 26.555 45.897 26.941 ;
     RECT  44.748 26.797 44.766 27.095 ;
     RECT  45.504 26.941 45.897 27.095 ;
     RECT  2.232 26.635 6.318 27.103 ;
     RECT  43.308 26.861 43.326 27.211 ;
     RECT  42.768 27.211 43.326 27.307 ;
     RECT  42.372 27.307 43.326 27.365 ;
     RECT  42.768 27.365 43.326 27.401 ;
     RECT  2.232 27.103 6.354 27.481 ;
     RECT  50.688 26.789 50.706 27.595 ;
     RECT  2.232 27.481 6.894 27.607 ;
     RECT  7.815 25.439 8.097 27.607 ;
     RECT  42.768 27.401 43.182 27.635 ;
     RECT  47.052 27.355 47.07 27.671 ;
     RECT  47.988 26.905 48.15 27.715 ;
     RECT  47.232 27.715 48.15 27.751 ;
     RECT  49.176 26.825 49.194 27.751 ;
     RECT  42.768 27.635 42.786 27.869 ;
     RECT  47.232 27.751 49.338 27.869 ;
     RECT  48.348 27.869 49.338 27.905 ;
     RECT  47.232 27.869 47.25 27.941 ;
     RECT  50.184 27.595 50.706 27.941 ;
     RECT  50.688 27.941 50.706 28.139 ;
     RECT  48.96 27.905 49.338 28.175 ;
     RECT  2.232 27.607 8.097 28.489 ;
     RECT  9.936 26.321 9.954 28.651 ;
     RECT  15.948 28.603 15.966 28.747 ;
     RECT  24.015 2.413 24.297 28.747 ;
     RECT  9.936 28.651 10.854 28.781 ;
     RECT  15.624 28.747 15.966 28.787 ;
     RECT  9.936 28.781 10.242 28.985 ;
     RECT  15.948 28.787 15.966 29.057 ;
     RECT  2.196 28.489 8.097 29.309 ;
     RECT  2.232 29.309 8.097 29.327 ;
     RECT  18.615 2.413 18.897 29.371 ;
     RECT  24.015 28.747 24.966 29.645 ;
     RECT  2.232 29.327 6.894 31.117 ;
     RECT  14.508 27.301 14.526 31.117 ;
     RECT  14.508 31.117 14.85 31.217 ;
     RECT  2.232 31.117 6.966 31.261 ;
     RECT  2.232 31.261 7.038 31.649 ;
     RECT  2.232 31.649 6.894 31.919 ;
     RECT  14.508 31.217 14.526 32.261 ;
     RECT  13.215 22.199 13.497 32.773 ;
     RECT  12.348 35.581 12.366 35.699 ;
     RECT  13.215 32.773 14.13 35.977 ;
     RECT  12.24 35.815 12.258 36.005 ;
     RECT  13.215 35.977 14.85 36.077 ;
     RECT  18.54 29.371 18.897 36.121 ;
     RECT  2.232 31.919 6.75 36.823 ;
     RECT  9.936 28.985 9.954 36.959 ;
     RECT  2.232 36.823 6.822 37.435 ;
     RECT  7.815 29.327 8.097 37.435 ;
     RECT  2.232 37.435 8.097 38.011 ;
     RECT  2.232 38.011 8.19 38.129 ;
     RECT  7.815 38.129 8.19 38.201 ;
     RECT  2.232 38.129 6.966 38.399 ;
     RECT  18.54 36.121 19.35 38.669 ;
     RECT  0.036 38.677 0.054 38.749 ;
     RECT  0.036 38.749 0.126 38.777 ;
     RECT  2.304 38.399 6.966 39.217 ;
     RECT  7.815 38.201 8.097 39.487 ;
     RECT  13.215 36.077 14.13 39.487 ;
     RECT  2.268 39.217 6.966 39.515 ;
     RECT  5.436 39.515 6.966 39.559 ;
     RECT  7.776 39.487 8.097 39.559 ;
     RECT  11.412 36.823 11.43 39.559 ;
     RECT  13.215 39.487 14.85 39.631 ;
     RECT  17.568 31.261 17.586 39.749 ;
     RECT  5.436 39.559 8.097 39.785 ;
     RECT  12.78 39.631 14.85 39.785 ;
     RECT  18.615 38.669 19.35 39.865 ;
     RECT  0.108 38.777 0.126 39.965 ;
     RECT  5.436 39.785 6.966 40.019 ;
     RECT  13.215 39.785 14.85 40.019 ;
     RECT  18 39.865 19.35 40.297 ;
     RECT  5.436 40.019 6.21 40.559 ;
     RECT  18 40.297 20.034 40.567 ;
     RECT  21.024 27.373 21.042 40.567 ;
     RECT  2.268 39.515 4.482 40.667 ;
     RECT  14.832 40.019 14.85 40.703 ;
     RECT  5.436 40.559 5.454 41.909 ;
     RECT  11.412 39.559 11.646 42.493 ;
     RECT  18 40.567 21.042 42.565 ;
     RECT  13.215 40.019 13.914 42.601 ;
     RECT  6.192 40.559 6.21 42.629 ;
     RECT  10.836 42.493 12.006 42.629 ;
     RECT  6.948 40.019 6.966 42.719 ;
     RECT  10.908 42.629 12.006 42.719 ;
     RECT  13.215 42.601 14.274 42.719 ;
     RECT  11.412 42.719 11.862 42.755 ;
     RECT  11.412 42.755 11.646 43.259 ;
     RECT  17.532 42.565 21.042 43.267 ;
     RECT  11.412 43.259 11.43 43.295 ;
     RECT  2.304 40.667 4.482 43.529 ;
     RECT  2.304 43.529 3.978 43.565 ;
     RECT  16.812 43.267 21.042 43.573 ;
     RECT  13.215 42.719 14.13 43.601 ;
     RECT  2.304 43.565 3.942 43.799 ;
     RECT  2.304 43.799 3.582 43.907 ;
     RECT  2.304 43.907 3.366 44.069 ;
     RECT  2.304 44.069 2.697 44.645 ;
     RECT  29.415 2.413 29.697 46.543 ;
     RECT  26.784 46.459 26.802 46.589 ;
     RECT  16.812 43.573 21.366 46.843 ;
     RECT  24.015 29.645 24.297 46.843 ;
     RECT  24.015 46.843 24.786 46.921 ;
     RECT  13.215 43.601 13.914 46.949 ;
     RECT  16.812 46.843 21.834 47.075 ;
     RECT  16.812 47.075 21.258 47.119 ;
     RECT  15.768 47.119 15.786 47.155 ;
     RECT  16.776 47.119 21.258 47.155 ;
     RECT  23.472 46.921 25.074 47.191 ;
     RECT  15.372 47.155 21.258 47.213 ;
     RECT  27.54 47.272 27.558 47.281 ;
     RECT  15.516 47.213 21.258 47.309 ;
     RECT  27.54 47.281 27.738 47.309 ;
     RECT  16.668 47.309 21.258 47.345 ;
     RECT  27.612 47.309 27.738 47.461 ;
     RECT  27.612 47.461 28.494 47.467 ;
     RECT  34.815 2.413 35.097 47.551 ;
     RECT  34.164 47.551 35.097 47.587 ;
     RECT  22.752 47.191 25.074 47.659 ;
     RECT  27.612 47.467 28.53 47.695 ;
     RECT  29.415 46.543 29.79 47.695 ;
     RECT  22.572 47.659 25.074 47.731 ;
     RECT  26.28 47.551 26.298 47.731 ;
     RECT  27.612 47.695 29.79 47.821 ;
     RECT  22.5 47.731 26.298 47.848 ;
     RECT  16.74 47.345 21.258 47.849 ;
     RECT  27.612 47.821 30.294 47.849 ;
     RECT  37.404 47.389 37.422 47.849 ;
     RECT  31.572 47.821 31.59 47.851 ;
     RECT  36.324 47.821 36.342 47.851 ;
     RECT  22.428 47.848 26.298 47.899 ;
     RECT  22.428 47.899 26.622 47.929 ;
     RECT  27.612 47.849 28.53 47.957 ;
     RECT  15.516 47.309 15.93 47.965 ;
     RECT  22.176 47.929 26.622 48.001 ;
     RECT  29.415 47.849 30.294 48.001 ;
     RECT  31.392 47.851 31.59 48.001 ;
     RECT  20.592 47.849 21.258 48.091 ;
     RECT  22.176 48.001 26.874 48.091 ;
     RECT  14.616 47.965 15.93 48.119 ;
     RECT  27.612 47.957 28.386 48.119 ;
     RECT  37.224 47.929 37.35 48.119 ;
     RECT  36.144 47.851 36.342 48.155 ;
     RECT  32.796 47.857 32.814 48.199 ;
     RECT  33.552 47.587 35.097 48.199 ;
     RECT  15.336 48.119 15.93 48.235 ;
     RECT  20.592 48.091 26.874 48.235 ;
     RECT  27.612 48.119 28.242 48.235 ;
     RECT  15.336 48.235 16.002 48.263 ;
     RECT  16.74 47.849 19.746 48.269 ;
     RECT  15.408 48.263 16.002 48.271 ;
     RECT  16.74 48.269 19.494 48.271 ;
     RECT  36.288 48.155 36.342 48.271 ;
     RECT  37.224 48.119 37.242 48.271 ;
     RECT  20.592 48.235 28.242 48.299 ;
     RECT  32.796 48.199 35.097 48.361 ;
     RECT  15.408 48.271 19.494 48.389 ;
     RECT  32.472 48.361 35.097 48.389 ;
     RECT  36.288 48.271 37.242 48.389 ;
     RECT  14.472 48.271 14.49 48.413 ;
     RECT  15.66 48.389 19.386 48.461 ;
     RECT  29.415 48.001 31.59 48.505 ;
     RECT  32.472 48.389 32.85 48.505 ;
     RECT  29.415 48.505 32.85 48.659 ;
     RECT  36.288 48.389 36.666 49.045 ;
     RECT  20.736 48.299 28.242 49.109 ;
     RECT  20.736 49.109 21.654 49.199 ;
     RECT  29.415 48.659 30.294 49.199 ;
     RECT  31.248 48.659 32.49 49.199 ;
     RECT  15.66 48.461 19.35 49.279 ;
     RECT  36.036 49.045 36.666 49.315 ;
     RECT  20.736 49.199 21.618 49.351 ;
     RECT  29.415 49.199 30.258 49.351 ;
     RECT  33.732 48.389 35.097 49.351 ;
     RECT  2.415 44.645 2.697 49.427 ;
     RECT  7.815 39.785 8.097 49.427 ;
     RECT  13.215 46.949 13.497 49.427 ;
     RECT  40.215 2.413 40.497 49.427 ;
     RECT  45.615 27.095 45.897 49.427 ;
     RECT  15.66 49.279 19.458 49.469 ;
     RECT  20.592 49.351 21.618 49.469 ;
     RECT  22.428 49.109 28.242 49.469 ;
     RECT  29.376 49.351 30.258 49.469 ;
     RECT  31.248 49.199 32.418 49.469 ;
     RECT  36.036 49.315 36.738 49.469 ;
     RECT  29.376 49.469 30.078 49.477 ;
     RECT  15.732 49.469 19.278 49.517 ;
     RECT  20.592 49.469 21.438 49.517 ;
     RECT  22.428 49.469 27.702 49.517 ;
     RECT  29.196 49.477 30.078 49.517 ;
     RECT  31.248 49.469 32.238 49.517 ;
     RECT  33.408 49.351 35.097 49.517 ;
     RECT  36.036 49.469 36.558 49.517 ;
     RECT  34.815 49.517 35.097 49.531 ;
     RECT  15.732 49.517 16.038 49.565 ;
     RECT  23.4 49.517 26.082 49.565 ;
     RECT  26.856 49.517 27.702 49.565 ;
     RECT  16.92 49.517 18.774 49.577 ;
     RECT  20.268 49.531 20.286 49.577 ;
     RECT  22.428 49.517 22.446 49.577 ;
     RECT  23.4 49.565 25.686 49.577 ;
     RECT  26.856 49.565 27.306 49.577 ;
     RECT  31.068 49.531 31.086 49.577 ;
     RECT  33.228 49.531 33.246 49.577 ;
     RECT  34.815 49.531 35.406 49.577 ;
     RECT  2.415 49.427 2.505 49.697 ;
     RECT  7.815 49.427 7.905 49.697 ;
     RECT  13.215 49.427 13.305 49.697 ;
     RECT  18.615 49.577 18.774 49.697 ;
     RECT  23.832 49.577 24.105 49.697 ;
     RECT  29.415 49.517 29.61 49.697 ;
     RECT  34.815 49.577 34.905 49.697 ;
     RECT  40.215 49.427 40.305 49.697 ;
     RECT  45.615 49.427 45.705 49.697 ;
     RECT  18.756 49.697 18.774 49.805 ;
     RECT  29.592 49.697 29.61 49.805 ;
     RECT  27.288 49.577 27.306 50.189 ;
     RECT  23.832 49.697 23.85 50.765 ;
    LAYER M4 ;
     RECT  0.06 8.832 0.133 42.984 ;
     RECT  0.133 7.968 0.179 42.984 ;
     RECT  0.133 43.968 0.181 43.992 ;
     RECT  0.179 9.6 0.227 42.984 ;
     RECT  0.227 9.6 2.245 21.384 ;
     RECT  0.227 22.656 2.245 34.2 ;
     RECT  0.179 7.968 2.285 7.992 ;
     RECT  0.181 43.968 2.293 44.472 ;
     RECT  2.245 9.6 2.365 34.2 ;
     RECT  0.227 35.184 2.365 42.12 ;
     RECT  2.365 9.6 2.401 42.12 ;
     RECT  2.285 7.968 2.408 8.52 ;
     RECT  2.401 9.6 2.408 42.744 ;
     RECT  2.293 43.92 2.408 44.472 ;
     RECT  2.408 2.148 2.512 49.692 ;
     RECT  2.512 2.418 2.704 49.422 ;
     RECT  2.704 8.352 2.837 40.968 ;
     RECT  2.837 8.352 2.845 31.128 ;
     RECT  2.704 41.952 2.867 42.984 ;
     RECT  2.837 32.256 2.873 40.968 ;
     RECT  2.873 32.256 2.917 40.824 ;
     RECT  2.917 32.256 2.981 40.2 ;
     RECT  2.981 32.256 3.059 39.384 ;
     RECT  2.845 8.496 3.299 31.128 ;
     RECT  2.867 41.952 3.347 41.976 ;
     RECT  2.867 42.96 3.347 42.984 ;
     RECT  3.299 8.496 3.485 9.912 ;
     RECT  3.299 11.04 3.683 31.128 ;
     RECT  3.683 11.04 3.701 13.656 ;
     RECT  3.485 8.496 3.731 8.52 ;
     RECT  3.485 9.888 3.779 9.912 ;
     RECT  3.683 14.736 3.805 31.128 ;
     RECT  3.059 32.256 3.805 37.128 ;
     RECT  3.805 14.736 3.809 37.128 ;
     RECT  3.809 14.784 3.953 37.128 ;
     RECT  3.701 11.04 3.971 13.56 ;
     RECT  3.953 14.784 4.061 32.616 ;
     RECT  3.971 13.056 4.067 13.56 ;
     RECT  4.061 15.072 4.097 32.616 ;
     RECT  3.971 11.04 4.163 11.88 ;
     RECT  4.067 13.056 4.241 13.512 ;
     RECT  4.097 15.072 4.259 31.464 ;
     RECT  3.953 33.6 4.277 37.128 ;
     RECT  3.059 38.544 4.277 39.384 ;
     RECT  4.277 33.6 4.307 35.784 ;
     RECT  4.241 13.488 4.355 13.512 ;
     RECT  4.259 19.968 4.385 31.464 ;
     RECT  4.097 32.448 4.403 32.616 ;
     RECT  4.165 42.768 4.403 42.792 ;
     RECT  4.093 40.464 4.451 40.488 ;
     RECT  4.259 15.072 4.493 18.888 ;
     RECT  4.307 33.6 4.493 35.352 ;
     RECT  4.277 37.104 4.525 37.128 ;
     RECT  4.493 15.072 4.547 17.064 ;
     RECT  4.385 23.376 4.565 31.464 ;
     RECT  4.385 19.968 4.595 22.248 ;
     RECT  4.565 23.376 4.595 25.608 ;
     RECT  4.547 15.552 4.601 17.064 ;
     RECT  4.493 33.696 4.601 35.352 ;
     RECT  4.595 23.376 4.673 23.448 ;
     RECT  4.601 33.696 4.673 35.304 ;
     RECT  4.673 33.696 4.745 34.152 ;
     RECT  4.673 23.424 4.781 23.448 ;
     RECT  4.595 20.64 4.817 22.248 ;
     RECT  4.817 20.736 4.835 22.248 ;
     RECT  4.673 35.28 4.853 35.304 ;
     RECT  4.277 38.928 4.889 39.384 ;
     RECT  4.493 18.048 5.027 18.888 ;
     RECT  4.835 20.736 5.033 21.96 ;
     RECT  5.027 18.24 5.105 18.888 ;
     RECT  4.565 26.784 5.113 31.464 ;
     RECT  4.163 11.04 5.123 11.064 ;
     RECT  5.113 27.264 5.177 31.464 ;
     RECT  4.601 15.552 5.321 16.536 ;
     RECT  5.033 20.736 5.393 20.76 ;
     RECT  4.595 24.48 5.411 25.272 ;
     RECT  5.177 27.792 5.429 31.464 ;
     RECT  5.429 30 5.465 31.464 ;
     RECT  5.465 30 5.501 30.36 ;
     RECT  5.429 27.792 5.555 29.016 ;
     RECT  4.525 37.104 5.605 37.656 ;
     RECT  5.501 30.288 5.651 30.36 ;
     RECT  5.465 31.44 5.681 31.464 ;
     RECT  4.889 39.312 5.681 39.384 ;
     RECT  5.605 37.056 5.689 37.656 ;
     RECT  5.105 18.24 5.717 18.744 ;
     RECT  5.321 15.552 5.747 15.576 ;
     RECT  5.411 25.104 5.747 25.272 ;
     RECT  4.403 32.448 5.753 32.472 ;
     RECT  5.756 35.856 5.843 35.88 ;
     RECT  5.689 37.104 5.843 37.656 ;
     RECT  5.717 18.24 5.897 18.648 ;
     RECT  5.843 37.392 5.897 37.656 ;
     RECT  5.651 30.288 5.933 30.312 ;
     RECT  5.897 18.528 5.939 18.648 ;
     RECT  5.747 25.104 5.939 25.128 ;
     RECT  5.939 18.528 6.185 18.552 ;
     RECT  5.897 37.632 6.293 37.656 ;
     RECT  5.033 21.792 7.808 21.96 ;
     RECT  5.555 28.656 7.808 29.016 ;
     RECT  6.709 38.016 7.808 38.184 ;
     RECT  5.681 39.312 7.808 39.336 ;
     RECT  7.808 2.148 7.912 49.692 ;
     RECT  7.912 2.418 8.104 49.422 ;
     RECT  8.104 28.752 10.213 29.016 ;
     RECT  10.213 28.656 10.865 29.016 ;
     RECT  8.104 21.792 13.208 21.96 ;
     RECT  10.865 28.752 13.208 29.016 ;
     RECT  13.208 2.148 13.312 49.692 ;
     RECT  13.312 2.418 13.504 49.422 ;
     RECT  13.504 28.752 15.301 29.016 ;
     RECT  15.205 47.184 15.401 47.208 ;
     RECT  15.301 28.752 15.925 29.544 ;
     RECT  15.925 28.608 16.012 29.544 ;
     RECT  13.504 48.384 16.301 48.408 ;
     RECT  15.692 49.536 16.597 49.56 ;
     RECT  16.597 49.488 16.697 49.56 ;
     RECT  17.521 48.192 17.665 48.216 ;
     RECT  17.665 47.808 18.061 48.216 ;
     RECT  18.061 46.848 18.457 48.216 ;
     RECT  13.504 21.936 18.608 22.056 ;
     RECT  15.925 27.312 18.608 27.336 ;
     RECT  16.012 28.752 18.608 29.544 ;
     RECT  18.457 46.848 18.608 48.408 ;
     RECT  16.697 49.536 18.608 49.56 ;
     RECT  18.608 2.148 18.712 49.692 ;
     RECT  18.712 2.418 18.716 49.692 ;
     RECT  18.716 2.418 18.803 49.8 ;
     RECT  18.803 2.418 18.904 49.512 ;
     RECT  18.904 46.848 19.217 47.064 ;
     RECT  18.904 49.488 19.289 49.512 ;
     RECT  18.904 48.192 19.649 48.408 ;
     RECT  19.649 48.24 19.757 48.408 ;
     RECT  18.904 21.936 19.829 21.96 ;
     RECT  19.217 46.848 20.053 46.872 ;
     RECT  20.053 46.656 20.14 46.872 ;
     RECT  20.156 22.128 20.243 22.152 ;
     RECT  20.257 49.536 20.531 49.56 ;
     RECT  19.757 48.384 20.765 48.408 ;
     RECT  20.917 49.488 21.449 49.512 ;
     RECT  21.013 48.432 22.417 48.456 ;
     RECT  20.14 46.848 22.693 46.872 ;
     RECT  22.417 47.856 22.693 48.456 ;
     RECT  22.693 46.848 22.739 48.456 ;
     RECT  22.739 46.848 22.781 48.264 ;
     RECT  22.781 47.856 22.925 48.264 ;
     RECT  22.417 49.536 23.077 49.56 ;
     RECT  23.821 50.736 23.987 50.76 ;
     RECT  20.197 25.584 24.008 25.608 ;
     RECT  18.904 27.312 24.008 27.336 ;
     RECT  18.904 28.752 24.008 29.544 ;
     RECT  22.781 46.848 24.008 46.872 ;
     RECT  22.925 48.24 24.008 48.264 ;
     RECT  23.077 49.488 24.008 49.56 ;
     RECT  24.008 2.148 24.112 49.692 ;
     RECT  24.112 2.418 24.304 49.56 ;
     RECT  24.304 46.464 24.803 46.872 ;
     RECT  24.304 28.752 24.977 29.64 ;
     RECT  24.304 47.904 24.977 48.264 ;
     RECT  24.977 29.616 25.091 29.64 ;
     RECT  24.803 46.464 25.091 46.728 ;
     RECT  24.977 47.904 25.369 48.024 ;
     RECT  24.304 49.536 26.533 49.56 ;
     RECT  25.369 47.856 26.633 48.024 ;
     RECT  26.533 49.488 26.633 49.56 ;
     RECT  25.091 46.464 26.725 46.488 ;
     RECT  26.725 46.464 26.813 47.304 ;
     RECT  26.633 49.536 27.277 49.56 ;
     RECT  26.665 48.336 27.317 48.36 ;
     RECT  27.277 49.536 27.443 50.184 ;
     RECT  27.443 49.536 27.875 49.56 ;
     RECT  26.813 46.56 28.069 47.304 ;
     RECT  24.304 25.584 29.408 25.608 ;
     RECT  24.304 27.312 29.408 27.336 ;
     RECT  28.069 46.56 29.408 47.88 ;
     RECT  29.125 49.488 29.408 49.512 ;
     RECT  29.408 2.148 29.512 49.692 ;
     RECT  29.512 2.418 29.557 49.692 ;
     RECT  29.557 2.418 29.644 49.8 ;
     RECT  29.644 2.418 29.704 49.512 ;
     RECT  29.704 46.56 29.801 46.584 ;
     RECT  29.704 49.488 30.089 49.512 ;
     RECT  31.057 49.536 31.331 49.56 ;
     RECT  31.717 49.488 32.249 49.512 ;
     RECT  33.217 49.536 33.491 49.56 ;
     RECT  29.704 47.856 34.357 47.88 ;
     RECT  33.877 49.488 34.357 49.512 ;
     RECT  29.704 25.584 34.808 25.608 ;
     RECT  29.704 27.312 34.808 27.336 ;
     RECT  34.357 47.856 34.808 49.512 ;
     RECT  34.808 2.148 34.912 49.692 ;
     RECT  34.912 2.418 35.104 49.56 ;
     RECT  35.104 49.488 35.651 49.56 ;
     RECT  35.104 47.856 36.173 47.88 ;
     RECT  35.651 49.488 36.569 49.512 ;
     RECT  35.104 25.584 40.208 25.608 ;
     RECT  35.104 27.312 40.208 27.336 ;
     RECT  40.208 2.148 40.312 49.692 ;
     RECT  40.312 2.418 40.504 49.422 ;
     RECT  40.504 27.312 42.757 27.336 ;
     RECT  42.757 27.216 42.797 27.336 ;
     RECT  40.504 25.584 43.909 25.608 ;
     RECT  42.797 27.216 43.916 27.24 ;
     RECT  43.909 25.104 43.949 25.608 ;
     RECT  43.916 26.736 43.957 27.24 ;
     RECT  43.957 26.736 44.003 27.384 ;
     RECT  43.949 25.104 45.529 25.128 ;
     RECT  45.529 24.624 45.608 25.128 ;
     RECT  45.493 26.256 45.608 26.28 ;
     RECT  44.003 27.36 45.608 27.384 ;
     RECT  45.608 2.148 45.712 49.692 ;
     RECT  45.712 2.418 45.904 49.422 ;
     RECT  45.904 24.624 46.892 24.648 ;
     RECT  46.892 23.904 46.979 24.648 ;
     RECT  45.904 27.36 47.081 27.384 ;
     RECT  46.933 25.68 47.189 25.704 ;
     RECT  49.597 26.736 50.173 26.76 ;
     RECT  50.173 26.736 50.641 27.624 ;
     RECT  50.641 25.008 50.677 25.032 ;
     RECT  50.641 26.304 50.677 27.624 ;
     RECT  50.677 24.576 50.713 27.624 ;
     RECT  50.713 24.144 51.804 27.624 ;
    LAYER M5 ;
     RECT  2.4 2.137 2.52 2.151 ;
     RECT  7.8 2.137 7.92 2.151 ;
     RECT  13.2 2.137 13.32 2.151 ;
     RECT  18.6 2.137 18.72 2.151 ;
     RECT  24 2.137 24.12 2.151 ;
     RECT  29.4 2.137 29.52 2.151 ;
     RECT  34.8 2.137 34.92 2.151 ;
     RECT  40.2 2.137 40.32 2.151 ;
     RECT  45.6 2.137 45.72 2.151 ;
     RECT  2.4 2.151 2.712 8.341 ;
     RECT  2.4 8.341 2.808 8.485 ;
     RECT  2.304 8.485 3.72 9.877 ;
     RECT  2.304 9.877 3.768 10.355 ;
     RECT  0.144 7.957 0.168 10.741 ;
     RECT  0.144 10.741 0.216 10.883 ;
     RECT  0.192 10.883 0.216 11.027 ;
     RECT  2.4 10.355 3.768 11.845 ;
     RECT  5.088 11.029 5.112 11.845 ;
     RECT  0.144 11.845 0.168 12.179 ;
     RECT  2.4 11.845 5.112 13.045 ;
     RECT  0.144 13.573 0.168 13.715 ;
     RECT  2.304 13.045 5.112 15.445 ;
     RECT  2.256 15.445 5.112 15.541 ;
     RECT  0.144 17.461 0.168 17.699 ;
     RECT  2.256 15.541 5.736 18.613 ;
     RECT  0.144 18.757 0.168 18.899 ;
     RECT  0.192 20.389 0.216 20.485 ;
     RECT  0.144 20.485 0.216 21.155 ;
     RECT  2.256 18.613 5.928 21.731 ;
     RECT  0.192 21.155 0.216 21.827 ;
     RECT  18.6 2.151 18.912 22.021 ;
     RECT  0.144 22.213 0.168 22.835 ;
     RECT  0.144 23.845 0.168 24.419 ;
     RECT  45.6 2.151 45.912 25.093 ;
     RECT  2.304 21.731 5.928 25.139 ;
     RECT  2.304 25.139 5.736 25.285 ;
     RECT  20.208 22.117 20.232 25.619 ;
     RECT  46.944 23.893 46.968 25.715 ;
     RECT  0.144 26.101 0.168 26.243 ;
     RECT  45.504 25.093 45.912 26.291 ;
     RECT  43.968 26.725 43.992 27.395 ;
     RECT  0.144 27.829 0.168 27.971 ;
     RECT  15.936 27.301 15.96 28.643 ;
     RECT  2.208 25.285 5.736 28.691 ;
     RECT  17.904 22.021 18.912 28.787 ;
     RECT  2.208 28.691 5.64 29.173 ;
     RECT  0.144 29.125 0.168 29.557 ;
     RECT  24 2.151 24.312 29.605 ;
     RECT  0.144 29.557 0.216 30.275 ;
     RECT  2.16 29.173 5.64 30.419 ;
     RECT  2.208 30.419 5.64 30.947 ;
     RECT  0.144 30.275 0.168 31.955 ;
     RECT  0.144 33.445 0.168 34.165 ;
     RECT  2.208 30.947 4.536 34.259 ;
     RECT  5.616 30.947 5.64 35.845 ;
     RECT  0.144 34.165 0.216 36.035 ;
     RECT  2.208 34.259 4.44 37.091 ;
     RECT  5.616 35.845 5.832 37.091 ;
     RECT  5.808 37.091 5.832 37.427 ;
     RECT  0.24 36.037 0.264 37.667 ;
     RECT  6.72 38.005 6.744 38.149 ;
     RECT  7.8 2.151 8.112 38.149 ;
     RECT  6.72 38.149 8.112 38.195 ;
     RECT  6.816 38.195 8.112 39.347 ;
     RECT  2.4 37.091 4.44 39.395 ;
     RECT  4.368 39.395 4.44 40.499 ;
     RECT  0.144 40.405 0.168 41.267 ;
     RECT  2.4 39.395 3.336 41.269 ;
     RECT  4.368 40.499 4.392 42.803 ;
     RECT  0.144 42.517 0.168 42.949 ;
     RECT  2.304 41.269 3.336 42.995 ;
     RECT  2.304 42.995 2.712 43.955 ;
     RECT  0.144 42.949 0.216 44.003 ;
     RECT  0.192 44.003 0.216 44.483 ;
     RECT  24 29.605 25.08 46.739 ;
     RECT  24 46.739 24.792 46.883 ;
     RECT  15.312 29.509 15.336 47.173 ;
     RECT  34.8 2.151 35.112 47.845 ;
     RECT  26.736 47.269 26.76 48.371 ;
     RECT  15.216 47.173 15.336 48.419 ;
     RECT  20.064 46.645 20.088 48.419 ;
     RECT  22.704 47.701 22.728 48.467 ;
     RECT  18.6 28.787 18.912 49.477 ;
     RECT  24 46.883 24.312 49.477 ;
     RECT  29.4 2.151 29.712 49.477 ;
     RECT  34.368 47.845 35.112 49.477 ;
     RECT  15.312 48.419 15.336 49.525 ;
     RECT  16.608 49.477 16.632 49.525 ;
     RECT  18.6 49.477 19.224 49.525 ;
     RECT  20.928 49.477 21.384 49.525 ;
     RECT  23.088 49.477 24.312 49.525 ;
     RECT  26.544 49.477 26.568 49.525 ;
     RECT  31.728 49.477 32.184 49.525 ;
     RECT  33.888 49.477 36.504 49.525 ;
     RECT  2.4 43.955 2.712 49.689 ;
     RECT  7.8 39.347 8.112 49.689 ;
     RECT  13.2 2.151 13.512 49.689 ;
     RECT  40.2 2.151 40.512 49.689 ;
     RECT  45.6 26.291 45.912 49.689 ;
     RECT  2.4 49.689 2.52 49.703 ;
     RECT  7.8 49.689 7.92 49.703 ;
     RECT  13.2 49.689 13.32 49.703 ;
     RECT  33.456 49.525 36.504 49.703 ;
     RECT  40.2 49.689 40.32 49.703 ;
     RECT  45.6 49.689 45.72 49.703 ;
     RECT  15.312 49.525 19.224 51.792 ;
     RECT  20.496 49.525 21.384 51.792 ;
     RECT  22.656 49.525 27.864 51.792 ;
     RECT  29.136 49.477 30.024 51.792 ;
     RECT  31.296 49.525 32.184 51.792 ;
     RECT  33.456 49.703 34.344 51.792 ;
     RECT  35.616 49.703 36.504 51.792 ;
     RECT  0.144 10.883 0.192 11.027 ;
     RECT  0.144 11.027 0.168 11.845 ;
     RECT  3.768 11.029 5.088 11.845 ;
     RECT  0.144 12.179 0.168 13.573 ;
     RECT  0.144 17.699 0.168 18.757 ;
     RECT  0.144 21.155 0.192 21.827 ;
     RECT  0.144 21.827 0.168 22.213 ;
     RECT  18.912 22.117 20.208 25.619 ;
     RECT  0.144 22.835 0.168 23.845 ;
     RECT  45.912 23.893 46.944 25.715 ;
     RECT  0.144 27.971 0.168 29.125 ;
     RECT  4.536 30.947 5.616 34.259 ;
     RECT  0.144 31.955 0.168 33.445 ;
     RECT  4.44 34.259 5.616 37.091 ;
     RECT  4.44 37.091 5.808 37.427 ;
     RECT  6.744 38.005 7.8 38.149 ;
     RECT  3.336 39.395 4.368 42.803 ;
     RECT  0.144 41.267 0.168 42.517 ;
     RECT  18.912 46.645 20.064 48.419 ;
     RECT  22.728 47.701 24 48.467 ;
     RECT  26.736 48.371 26.76 49.477 ;
     RECT  18.912 48.419 20.088 49.477 ;
     RECT  22.704 48.467 24 49.477 ;
     RECT  15.336 49.477 16.608 49.525 ;
     RECT  19.224 49.477 20.928 49.525 ;
     RECT  21.384 49.477 23.088 49.525 ;
     RECT  26.568 49.477 26.76 49.525 ;
     RECT  19.224 49.525 20.496 51.708 ;
     RECT  21.384 49.525 22.656 51.708 ;
     RECT  27.864 49.525 29.136 51.708 ;
     RECT  30.024 49.525 31.296 51.708 ;
     RECT  32.184 49.525 33.456 51.708 ;
     RECT  34.344 49.703 35.616 51.708 ;
     RECT  19.272 51.708 19.584 51.792 ;
     RECT  19.704 51.708 20.016 51.792 ;
     RECT  20.136 51.708 20.448 51.792 ;
     RECT  21.432 51.708 21.744 51.792 ;
     RECT  21.864 51.708 22.176 51.792 ;
     RECT  22.296 51.708 22.608 51.792 ;
     RECT  27.912 51.708 28.224 51.792 ;
     RECT  28.344 51.708 28.656 51.792 ;
     RECT  28.776 51.708 29.088 51.792 ;
     RECT  30.072 51.708 30.384 51.792 ;
     RECT  30.504 51.708 30.816 51.792 ;
     RECT  30.936 51.708 31.248 51.792 ;
     RECT  32.232 51.708 32.544 51.792 ;
     RECT  32.664 51.708 32.976 51.792 ;
     RECT  33.096 51.708 33.408 51.792 ;
     RECT  34.392 51.708 34.704 51.792 ;
     RECT  34.824 51.708 35.136 51.792 ;
     RECT  35.256 51.708 35.568 51.792 ;
  END
END dsfd_vm_static_read_v0_p
END LIBRARY
